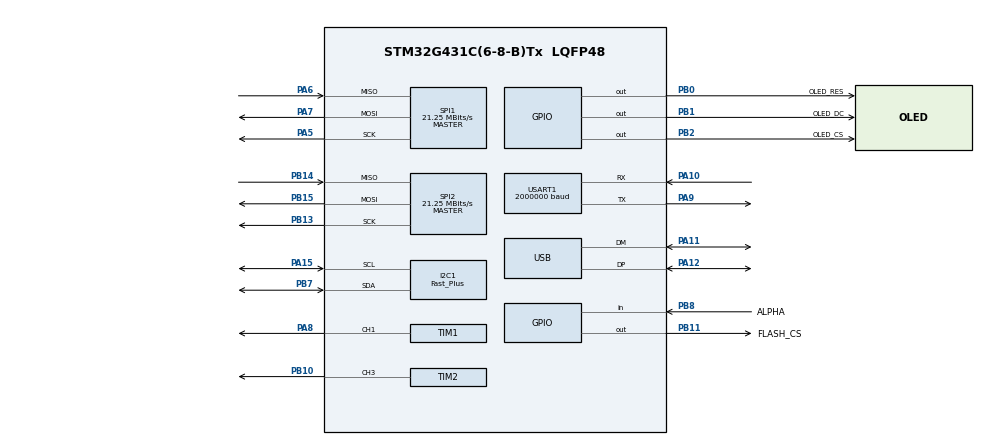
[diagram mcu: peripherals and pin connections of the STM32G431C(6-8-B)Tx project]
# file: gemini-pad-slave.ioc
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ADC1.Channel-0\#ChannelRegularConversion=ADC_CHANNEL_TEMPSENSOR_ADC1
ADC1.ContinuousConvMode=ENABLE
ADC1.DMAContinuousRequests=ENABLE
ADC1.EOCSelection=ADC_EOC_SINGLE_CONV
ADC1.NbrOfConversionFlag=1
ADC1.OffsetNumber-0\#ChannelRegularConversion=ADC_OFFSET_NONE
ADC1.Rank-0\#ChannelRegularConversion=1
ADC1.SamplingTime-0\#ChannelRegularConversion=ADC_SAMPLETIME_640CYCLES_5
ADC1.master=1
Dma.ADC1.2.Direction=DMA_PERIPH_TO_MEMORY
Dma.ADC1.2.EventEnable=DISABLE
Dma.ADC1.2.Instance=DMA1_Channel3
Dma.ADC1.2.MemDataAlignment=DMA_MDATAALIGN_WORD
Dma.ADC1.2.MemInc=DMA_MINC_ENABLE
Dma.ADC1.2.Mode=DMA_CIRCULAR
Dma.ADC1.2.PeriphDataAlignment=DMA_PDATAALIGN_WORD
Dma.ADC1.2.PeriphInc=DMA_PINC_DISABLE
Dma.ADC1.2.Polarity=HAL_DMAMUX_REQ_GEN_RISING
Dma.ADC1.2.Priority=DMA_PRIORITY_LOW
Dma.ADC1.2.RequestNumber=1
Dma.ADC1.2.SignalID=NONE
Dma.ADC1.2.SyncEnable=DISABLE
Dma.ADC1.2.SyncPolarity=HAL_DMAMUX_SYNC_NO_EVENT
Dma.ADC1.2.SyncRequestNumber=1
Dma.ADC1.2.SyncSignalID=NONE
Dma.Request0=USART1_RX
Dma.Request1=USART1_TX
Dma.Request2=ADC1
Dma.USART1_RX.0.Direction=DMA_PERIPH_TO_MEMORY
Dma.USART1_RX.0.EventEnable=DISABLE
Dma.USART1_RX.0.Instance=DMA1_Channel1
Dma.USART1_RX.0.MemDataAlignment=DMA_MDATAALIGN_BYTE
Dma.USART1_RX.0.MemInc=DMA_MINC_ENABLE
Dma.USART1_RX.0.Mode=DMA_NORMAL
Dma.USART1_RX.0.PeriphDataAlignment=DMA_PDATAALIGN_BYTE
Dma.USART1_RX.0.PeriphInc=DMA_PINC_DISABLE
Dma.USART1_RX.0.Polarity=HAL_DMAMUX_REQ_GEN_RISING
Dma.USART1_RX.0.Priority=DMA_PRIORITY_VERY_HIGH
Dma.USART1_RX.0.RequestNumber=1
Dma.USART1_RX.0.SignalID=NONE
Dma.USART1_RX.0.SyncEnable=DISABLE
Dma.USART1_RX.0.SyncPolarity=HAL_DMAMUX_SYNC_NO_EVENT
Dma.USART1_RX.0.SyncRequestNumber=1
Dma.USART1_RX.0.SyncSignalID=NONE
Dma.USART1_TX.1.Direction=DMA_MEMORY_TO_PERIPH
Dma.USART1_TX.1.EventEnable=DISABLE
Dma.USART1_TX.1.Instance=DMA1_Channel2
Dma.USART1_TX.1.MemDataAlignment=DMA_MDATAALIGN_BYTE
Dma.USART1_TX.1.MemInc=DMA_MINC_ENABLE
Dma.USART1_TX.1.Mode=DMA_NORMAL
Dma.USART1_TX.1.PeriphDataAlignment=DMA_PDATAALIGN_BYTE
Dma.USART1_TX.1.PeriphInc=DMA_PINC_DISABLE
Dma.USART1_TX.1.Polarity=HAL_DMAMUX_REQ_GEN_RISING
Dma.USART1_TX.1.Priority=DMA_PRIORITY_VERY_HIGH
Dma.USART1_TX.1.RequestNumber=1
Dma.USART1_TX.1.SignalID=NONE
Dma.USART1_TX.1.SyncEnable=DISABLE
Dma.USART1_TX.1.SyncPolarity=HAL_DMAMUX_SYNC_NO_EVENT
Dma.USART1_TX.1.SyncRequestNumber=1
Dma.USART1_TX.1.SyncSignalID=NONE
I2C1.I2C_Speed_Mode=I2C_Fast_Plus
I2C1.Timing=0x00802172
Mcu.Family=STM32G4
Mcu.Name=STM32G431C(6-8-B)Tx
Mcu.Package=LQFP48
NVIC.DMA1_Channel1_IRQn=true\:0\:0\:false\:false\:true\:false\:true\:true
NVIC.DMA1_Channel2_IRQn=true\:0\:0\:false\:false\:true\:false\:true\:true
NVIC.DMA1_Channel3_IRQn=true\:0\:0\:false\:false\:true\:false\:true\:true
NVIC.I2C1_ER_IRQn=true\:0\:0\:false\:false\:true\:true\:true\:true
NVIC.I2C1_EV_IRQn=true\:3\:0\:true\:false\:true\:true\:true\:true
NVIC.PriorityGroup=NVIC_PRIORITYGROUP_4
NVIC.TIM6_DAC_IRQn=true\:0\:0\:false\:false\:true\:true\:true\:true
NVIC.TIM7_IRQn=true\:0\:0\:false\:false\:true\:true\:true\:true
NVIC.USART1_IRQn=true\:3\:0\:true\:false\:true\:true\:true\:true
NVIC.USB_LP_IRQn=true\:0\:0\:false\:false\:true\:false\:true\:true
PA10.GPIO_ModeDefaultOD=GPIO_MODE_AF_PP
PA10.GPIO_Speed=GPIO_SPEED_FREQ_HIGH
PA10.Mode=Multiprocessor_communication
PA10.Signal=USART1_RX
PA11.Mode=Device
PA11.Signal=USB_DM
PA12.Mode=Device
PA12.Signal=USB_DP
PA13.Mode=Serial_Wire
PA13.Signal=SYS_JTMS-SWDIO
PA14.Mode=Serial_Wire
PA14.Signal=SYS_JTCK-SWCLK
PA15.Mode=I2C
PA15.Signal=I2C1_SCL
PA5.Mode=Full_Duplex_Master
PA5.Signal=SPI1_SCK
PA6.Mode=Full_Duplex_Master
PA6.Signal=SPI1_MISO
PA7.Mode=Full_Duplex_Master
PA7.Signal=SPI1_MOSI
PA8.Signal=S_TIM1_CH1
PA9.GPIO_ModeDefaultOD=GPIO_MODE_AF_PP
PA9.GPIO_Speed=GPIO_SPEED_FREQ_HIGH
PA9.Mode=Multiprocessor_communication
PA9.Signal=USART1_TX
PB0.GPIO_Label=OLED_RES
PB0.Signal=GPIO_Output
PB1.GPIO_Label=OLED_DC
PB1.Signal=GPIO_Output
PB10.Signal=S_TIM2_CH3
PB11.GPIO_Label=FLASH_CS
PB11.Signal=GPIO_Output
PB13.Mode=Full_Duplex_Master
PB13.Signal=SPI2_SCK
PB14.Mode=Full_Duplex_Master
PB14.Signal=SPI2_MISO
PB15.Mode=Full_Duplex_Master
PB15.Signal=SPI2_MOSI
PB2.GPIO_Label=OLED_CS
PB2.Signal=GPIO_Output
PB7.Mode=I2C
PB7.Signal=I2C1_SDA
PB8-BOOT0.GPIO_Label=ALPHA
PB8-BOOT0.Signal=GPIO_Input
PF0-OSC_IN.Mode=HSE-External-Oscillator
PF0-OSC_IN.Signal=RCC_OSC_IN
PF1-OSC_OUT.Mode=HSE-External-Oscillator
PF1-OSC_OUT.Signal=RCC_OSC_OUT
ProjectManager.HeapSize=0x200
ProjectManager.StackSize=0x400
ProjectManager.TargetToolchain=STM32CubeIDE
RCC.ADC12Freq_Value=170000000
RCC.AHBFreq_Value=170000000
RCC.APB1Freq_Value=170000000
RCC.APB1TimFreq_Value=170000000
RCC.APB2Freq_Value=170000000
RCC.APB2TimFreq_Value=170000000
RCC.CK48CLockSelection=RCC_USBCLKSOURCE_HSI48
RCC.CortexFreq_Value=170000000
RCC.EXTERNAL_CLOCK_VALUE=12288000
RCC.HCLKFreq_Value=170000000
RCC.HSE_VALUE=8000000
RCC.HSI48_VALUE=48000000
RCC.HSI_VALUE=16000000
RCC.LSE_VALUE=32768
RCC.PLLM=RCC_PLLM_DIV2
RCC.PLLN=85
RCC.PLLSourceVirtual=RCC_PLLSOURCE_HSE
RCC.SYSCLKFreq_VALUE=170000000
RCC.SYSCLKSource=RCC_SYSCLKSOURCE_PLLCLK
RCC.USBFreq_Value=48000000
RCC.VCOOutputFreq_Value=340000000
SH.S_TIM1_CH1.0=TIM1_CH1,PWM Generation1 CH1
SH.S_TIM2_CH3.0=TIM2_CH3,PWM Generation3 CH3
SPI1.BaudRatePrescaler=SPI_BAUDRATEPRESCALER_8
SPI1.CLKPhase=SPI_PHASE_2EDGE
SPI1.CLKPolarity=SPI_POLARITY_HIGH
SPI1.CalculateBaudRate=21.25 MBits/s
SPI1.DataSize=SPI_DATASIZE_8BIT
SPI1.Direction=SPI_DIRECTION_2LINES
SPI1.Mode=SPI_MODE_MASTER
SPI1.VirtualType=VM_MASTER
SPI2.BaudRatePrescaler=SPI_BAUDRATEPRESCALER_8
SPI2.CalculateBaudRate=21.25 MBits/s
SPI2.DataSize=SPI_DATASIZE_8BIT
SPI2.Direction=SPI_DIRECTION_2LINES
SPI2.Mode=SPI_MODE_MASTER
SPI2.VirtualType=VM_MASTER
TIM1.Channel-PWM\ Generation1\ CH1=TIM_CHANNEL_1
TIM2.Channel-PWM\ Generation3\ CH3=TIM_CHANNEL_3
TIM6.PeriodNoDither=10000-1
TIM6.Prescaler=17000-1
TIM7.PeriodNoDither=10000-1
TIM7.Prescaler=100-1
USART1.AutoBaudRateEnableParam=UART_ADVFEATURE_AUTOBAUDRATE_DISABLE
USART1.BaudRate=2000000
USART1.Parity=PARITY_EVEN
USART1.VirtualMode-Multiprocessor_communication=VM_ASYNC
USART1.WordLength=WORDLENGTH_9B
USB_DEVICE.CLASS_NAME_FS=CUSTOM_HID
USB_DEVICE.CUSTOM_HID_FS_BINTERVAL=0x1
USB_DEVICE.USBD_CUSTOMHID_OUTREPORT_BUF_SIZE=64
USB_DEVICE.USBD_CUSTOM_HID_REPORT_DESC_SIZE=33
USB_DEVICE.VirtualMode=CustomHid
USB_DEVICE.VirtualModeFS=Custom_Hid_FS
VP_ADC1_TempSens_Input.Mode=IN-TempSens
VP_SYS_VS_DBSignals.Mode=DisableDeadBatterySignals
VP_TIM6_VS_ClockSourceINT.Mode=Enable_Timer
VP_TIM7_VS_ClockSourceINT.Mode=Enable_Timer
VP_USB_DEVICE_VS_USB_DEVICE_CUSTOM_HID_FS.Mode=CUSTOM_HID_FS
board=custom

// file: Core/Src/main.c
/* USER CODE BEGIN Header */
/**
  ******************************************************************************
  * @file           : main.c
  * @brief          : Main program body
  ******************************************************************************
  * @attention
  *
  * Copyright (c) 2023 STMicroelectronics.
  * All rights reserved.
  *
  * This software is licensed under terms that can be found in the LICENSE file
  * in the root directory of this software component.
  * If no LICENSE file comes with this software, it is provided AS-IS.
  *
  ******************************************************************************
  */
/* USER CODE END Header */
#include "main.h"
#include "adc.h"
#include "dma.h"
#include "i2c.h"
#include "spi.h"
#include "tim.h"
#include "usart.h"
#include "usb_device.h"
#include "gpio.h"

/* USER CODE BEGIN Includes */

#include "stdio.h"
#include "stdlib.h"
//#include "uart_rec.h"
#include "fezui.h"
#include "fezui_var.h"
#include "display.h"
#include "communication.h"
#include "driver_w25qxx_advance.h"
/* USER CODE END Includes */

void SystemClock_Config(void);
/* USER CODE BEGIN PFP */
void MX_GPIO_Init();
void MX_DMA_Init();
void MX_I2C1_Init();
void MX_SPI1_Init();
void MX_SPI2_Init();
void MX_USB_Device_Init();
/* USER CODE END PFP */

/* USER CODE BEGIN 0 */

/**
 * @brief  This function provides a delay (in microseconds)
 * @param  microseconds: delay in microseconds
 */
void DWT_Delay_us(volatile uint32_t microseconds)
{
  uint32_t clk_cycle_start = DWT->CYCCNT;

  /* Go to number of cycles for system */
  microseconds *= (HAL_RCC_GetHCLKFreq() / 1000000);

  /* Delay till end */
  while ((DWT->CYCCNT - clk_cycle_start) < microseconds);
}

/* USER CODE END 0 */

int main(void)
{

  /* MCU Configuration--------------------------------------------------------*/

  /* Reset of all peripherals, Initializes the Flash interface and the Systick. */
  HAL_Init();

  /* Configure the system clock */
  SystemClock_Config();

  /* USER CODE BEGIN SysInit */
  //HAL_Delay(500);
  /* USER CODE END SysInit */

  /* Initialize all configured peripherals */
  MX_GPIO_Init();
  MX_DMA_Init();
  MX_I2C1_Init();
  MX_SPI1_Init();
  MX_SPI2_Init();
  MX_TIM1_Init();
  MX_TIM2_Init();
  MX_USART1_UART_Init();
  MX_USB_Device_Init();
  MX_TIM6_Init();
  MX_TIM7_Init();
  MX_ADC1_Init();
  /* USER CODE BEGIN 2 */
  w25qxx_advance_init(W25Q128, W25QXX_INTERFACE_SPI, W25QXX_BOOL_FALSE);
  fezui_init();
  HAL_ADCEx_Calibration_Start(&hadc1, ADC_SINGLE_ENDED);
  HAL_TIM_PWM_Start(&htim1,TIM_CHANNEL_1);
  //HAL_TIM_Base_Start_IT(&htim3);
  HAL_TIM_Base_Start_IT(&htim6);
  HAL_TIM_Base_Start_IT(&htim7);
  HAL_ADC_Start_DMA(&hadc1, &fezui_temp_raw, 1);

  Communication_Enable(&huart1,USART1_RX_Buffer,BUFFER_LENGTH);
  /* USER CODE END 2 */

  /* Infinite loop */
  /* USER CODE BEGIN WHILE */
  while (1)
  {
    fezui_render_handler();
    /* USER CODE END WHILE */

  }
}

void SystemClock_Config(void)
{
  RCC_OscInitTypeDef RCC_OscInitStruct = {0};
  RCC_ClkInitTypeDef RCC_ClkInitStruct = {0};

  /** Configure the main internal regulator output voltage
  */
  HAL_PWREx_ControlVoltageScaling(PWR_REGULATOR_VOLTAGE_SCALE1_BOOST);

  /** Initializes the RCC Oscillators according to the specified parameters
  * in the RCC_OscInitTypeDef structure.
  */
  RCC_OscInitStruct.OscillatorType = RCC_OSCILLATORTYPE_HSI48|RCC_OSCILLATORTYPE_HSE;
  RCC_OscInitStruct.HSEState = RCC_HSE_ON;
  RCC_OscInitStruct.HSI48State = RCC_HSI48_ON;
  RCC_OscInitStruct.PLL.PLLState = RCC_PLL_ON;
  RCC_OscInitStruct.PLL.PLLSource = RCC_PLLSOURCE_HSE;
  RCC_OscInitStruct.PLL.PLLM = RCC_PLLM_DIV1;
  RCC_OscInitStruct.PLL.PLLN = 42;
  RCC_OscInitStruct.PLL.PLLP = RCC_PLLP_DIV2;
  RCC_OscInitStruct.PLL.PLLQ = RCC_PLLQ_DIV2;
  RCC_OscInitStruct.PLL.PLLR = RCC_PLLR_DIV2;
  if (HAL_RCC_OscConfig(&RCC_OscInitStruct) != HAL_OK)
  {
    Error_Handler();
  }

  /** Initializes the CPU, AHB and APB buses clocks
  */
  RCC_ClkInitStruct.ClockType = RCC_CLOCKTYPE_HCLK|RCC_CLOCKTYPE_SYSCLK
                              |RCC_CLOCKTYPE_PCLK1|RCC_CLOCKTYPE_PCLK2;
  RCC_ClkInitStruct.SYSCLKSource = RCC_SYSCLKSOURCE_PLLCLK;
  RCC_ClkInitStruct.AHBCLKDivider = RCC_SYSCLK_DIV1;
  RCC_ClkInitStruct.APB1CLKDivider = RCC_HCLK_DIV1;
  RCC_ClkInitStruct.APB2CLKDivider = RCC_HCLK_DIV1;

  if (HAL_RCC_ClockConfig(&RCC_ClkInitStruct, FLASH_LATENCY_4) != HAL_OK)
  {
    Error_Handler();
  }
}

/* USER CODE BEGIN 4 */

void HAL_TIM_PeriodElapsedCallback(TIM_HandleTypeDef *htim)
{
    if (htim->Instance == TIM7)
    {
        fezui_timer_handler();
        //HAL_IWDG_Refresh(&hiwdg);
    }
    if (htim->Instance == TIM6)
    {
        sprintf(fpsstr, "%3ld", fezui_fps);
        sprintf(comstr, "%4ld", USART1_RX_Count);
        if (fezui.screensaver_countdown)
            fezui.screensaver_countdown--;
        lefl_loop_array_push_back(&KPS_history, UI_KPSMaximumPerSecond);
        if(USART1_RX_Count<500)
        {
            __HAL_UART_CLEAR_IDLEFLAG(&huart1);
            HAL_UART_DMAStop(&huart1);
            HAL_UART_DeInit(&huart1);
            MX_USART1_UART_Init();
            Communication_Enable(&huart1,USART1_RX_Buffer,BUFFER_LENGTH);
        }
        USART1_RX_Count=0;
        fezui_fps = 0;
        UI_KPSMaximumPerSecond = 0;
        fezui_run_time++;
        //fezui_save_counts();
    }
}

/* USER CODE END 4 */

void Error_Handler(void)
{
  __disable_irq();
  while (1)
  {
  }
}
